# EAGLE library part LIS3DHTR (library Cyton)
Accelerometer 3-Axis 2g/16g 1.8V LGA16 STMicroelectronics LIS3DHTR Accelerometer IC, 3-axis, I2C, SPI 1.71 3.6 V, 16-Pin LGA Source: Datasheet

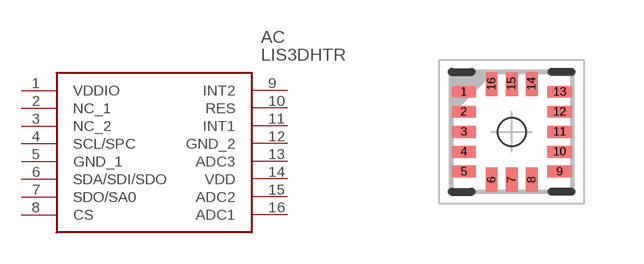
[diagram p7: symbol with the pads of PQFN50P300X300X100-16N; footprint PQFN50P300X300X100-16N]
Designator prefix AC

## LIS3DHTR (ALLIED_NUMBER: 70521157; DESCRIPTION: Accelerometer 3-Axis 2g/16g 1.8V LGA16 STMicroelectronics LIS3DHTR Accelerometer IC, 3-axis, I2C, SPI 1.71 3.6 V, 16-Pin LGA; HEIGHT: 1mm; MANUFACTURER_NAME: STMicroelectronics; MANUFACTURER_PART_NUMBER: LIS3DHTR; RS_PART_NUMBER: 7931364P; RS_PRICE-STOCK: http://uk.rs-online.com/web/p/products/7931364P)  [PQFN50P300X300X100-16N]
1  VDDIO  pwr
2  NC_1
3  NC_2
4  SCL/SPC
5  GND_1  pwr
6  SDA/SDI/SDO
7  SDO/SA0
8  CS  in
9  INT2  in
10  RES
11  INT1  in
12  GND_2  pwr
13  ADC3
14  VDD  pwr
15  ADC2
16  ADC1

## Footprint PQFN50P300X300X100-16N (pad centres in mm)
LGA-16_2
smd 0.6 x 0.3: 1 -1.2,1; 2 -1.2,0.5; 3 -1.2,0; 4 -1.2,-0.5; 5 -1.2,-1; 9 1.2,-1; 10 1.2,-0.5; 11 1.2,0; 12 1.2,0.5; 13 1.2,1
smd 0.3 x 0.6: 6 -0.5,-1.2; 7 0,-1.2; 8 0.5,-1.2; 14 0.5,1.2; 15 0,1.2; 16 -0.5,1.2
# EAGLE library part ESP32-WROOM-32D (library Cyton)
IC: SoC; GPIO, I2C, I2S, IR, SD, SDIO, SPI, UART; 2.7÷3.6VDC; 20dBm

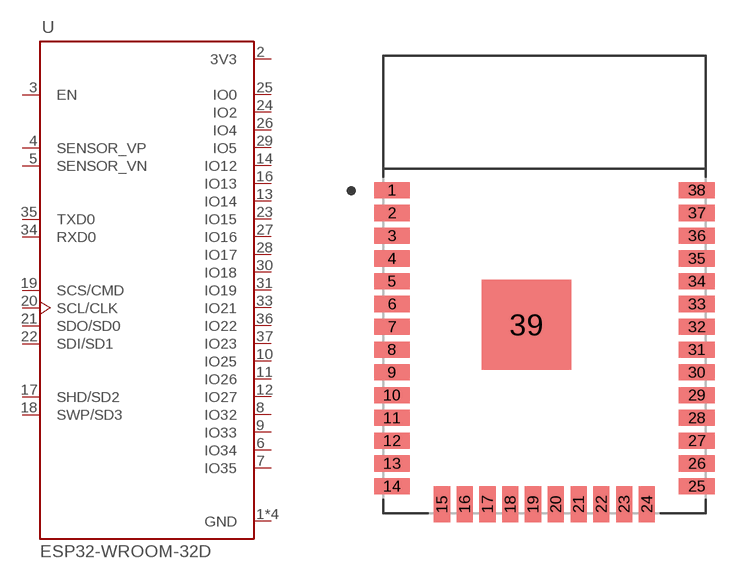
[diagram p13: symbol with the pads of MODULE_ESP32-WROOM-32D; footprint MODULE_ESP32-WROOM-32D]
Designator prefix U

## ESP32-WROOM-32D (AVAILABILITY: Unavailable; DESCRIPTION: IC: SoC; GPIO, I2C, I2S, IR, SD, SDIO, SPI, UART; 2.7÷3.6VDC; 20dBm; MF: Espressif Systems; MP: ESP32-WROOM-32D; PACKAGE: Module Espressif Systems; PRICE: None)  [MODULE_ESP32-WROOM-32D]
1  GND  pwr
2  3V3  pwr
3  EN  in
4  SENSOR_VP  in
5  SENSOR_VN  in
6  IO34
7  IO35
8  IO32
9  IO33
10  IO25
11  IO26
12  IO27
13  IO14
14  IO12
15  GND  pwr
16  IO13
17  SHD/SD2
18  SWP/SD3
19  SCS/CMD
20  SCL/CLK
21  SDO/SD0
22  SDI/SD1
23  IO15
24  IO2
25  IO0
26  IO4
27  IO16
28  IO17
29  IO5
30  IO18
31  IO19
33  IO21
34  RXD0
35  TXD0
36  IO22
37  IO23
38  GND  pwr
39  GND  pwr

## Footprint MODULE_ESP32-WROOM-32D (pad centres in mm)
smd 2 x 0.9: 1 -8.5,5.26; 2 -8.5,3.99; 3 -8.5,2.72; 4 -8.5,1.45; 5 -8.5,0.18; 6 -8.5,-1.09; 7 -8.5,-2.36; 8 -8.5,-3.63; 9 -8.5,-4.9; 10 -8.5,-6.17; 11 -8.5,-7.44; 12 -8.5,-8.71; 13 -8.5,-9.98; 14 -8.5,-11.25; 25 8.5,-11.25; 26 8.5,-9.98; 27 8.5,-8.71; 28 8.5,-7.44; 29 8.5,-6.17; 30 8.5,-4.9; 31 8.5,-3.63; 32 8.5,-2.36; 33 8.5,-1.09; 34 8.5,0.18; 35 8.5,1.45; 36 8.5,2.72; 37 8.5,3.99; 38 8.5,5.26
smd 0.9 x 2: 15 -5.715,-12.25; 16 -4.445,-12.25; 17 -3.175,-12.25; 18 -1.905,-12.25; 19 -0.635,-12.25; 20 0.635,-12.25; 21 1.905,-12.25; 22 3.175,-12.25; 23 4.445,-12.25; 24 5.715,-12.25
smd 5 x 5: 39 -1,-2.24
